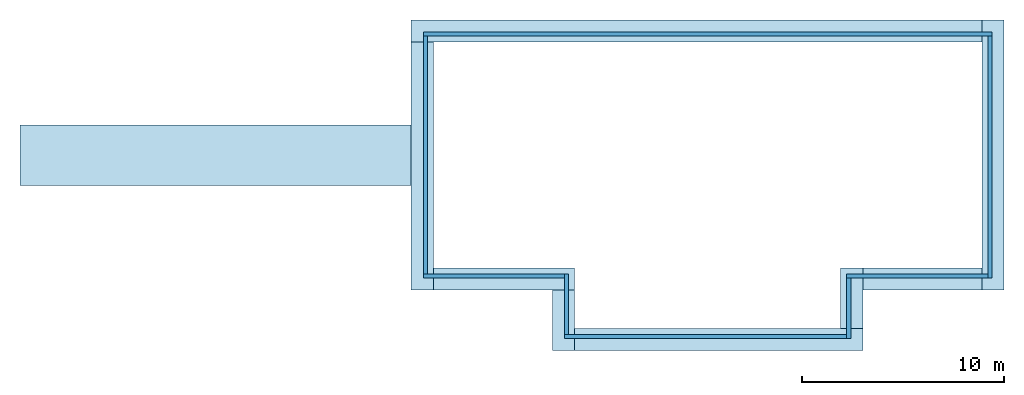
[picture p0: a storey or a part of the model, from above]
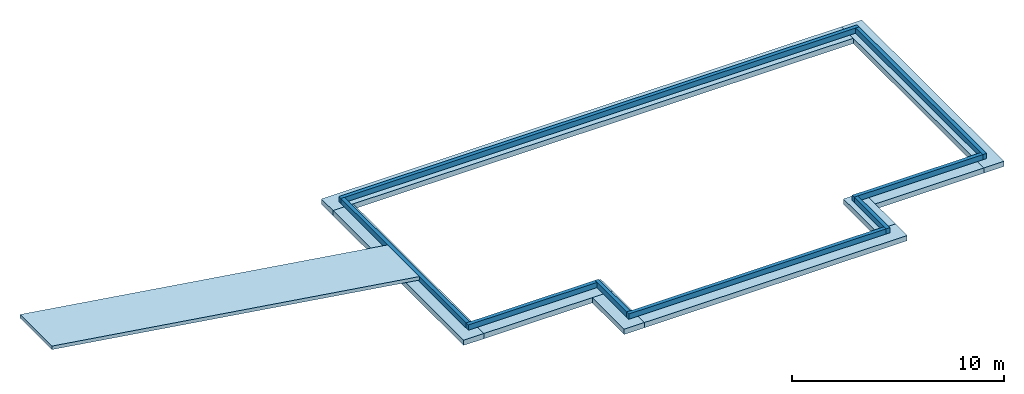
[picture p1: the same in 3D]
Properties of the parts of a building model (IFC2X3)

# File
Description: ViewDefinition [CoordinationView_V2.0, QuantityTakeOffAddOnView]
File name: Numéro de projet
Time: 2019-03-26T10:58:15
Written by: The EXPRESS Data Manager Version 5.02.0100.07 : 28 Aug 2013
Made in: 20180328_1600(x64) - Exporter 19.0.1.1 - Interface utilisateur alternative 19.0.1.1
Comment: STEP Physical File produced by: The EXPRESS Data Manager Version 5.02.0100.07 : 28 Aug 2013 * Module: EDMstepFileFactory/EDMstandAlone * Creation date: Tue Mar 26 10:58:15 2019 * Host: OCULUS-DGC * Database: C:\Users\TECHNI~1\AppData\Local\Temp\{1B9414DD-D0EE-45FC-AFBC-01F365118FDD}\ifc * Database version: 5507 * Database creation date: Tue Mar 26 10:58:10 2019 * Schema: IFC2X3 * Model: DataRepository.ifc * Model creation date: Tue Mar 26 10:58:10 2019 * Header model: DataRepository.ifc_HeaderModel * Header model creation date: Tue Mar 26 10:58:10 2019 * EDMuser: sdai-user * EDMgroup: sdai-group * License ID and type: 5605 : Permanent license. Expiry date: * EDMstepFileFactory options: 020000

# IfcProject, Numéro de projet
LongName: Nom du projet; Phase: Etat du projet

# IfcSite, Default
RefLatitude: 48, 51, 57, 604064; RefLongitude: 2, 19, 58, 799800; RefElevation: 0 m

# IfcBuilding
Pset_BuildingCommon - NumberOfStoreys: 9

# IfcBuildingStorey (9)
Name | LongName | Elevation (m)
Fondations | Fondations | -3.3
R-1 | R-1 | -3
Rez de Chaussée | Rez de Chaussée | 0
R+1 | R+1 | 3
R+2 | R+2 | 6
R+3 | R+3 | 9
R+4 | R+4 | 12
R+5 | R+5 | 15
R+6 | R+6 | 18

# IfcDoor: 1000 x 2000 mm (37)
Type - ParameterTakesPrecedence: no; Sizeable: no
OverallHeight: 2 m; OverallWidth: 1 m
Pset_DoorCommon - IsExternal: yes; Reference: 1000 x 2000 mm
BaseQuantities - Height: 2 m; Width: 1 m; Area: 2 m2
Name (M_Porte-Ouverture:1000 x 2000 mm:...) | In
454101 | R+1
454180 | R+1
454294 | R+1
454342 | R+1
454432 | R+1
454526 | R+1
456298 | R+2
456299 | R+2
456300 | R+2
456301 | R+2
456302 | R+2
456303 | R+2
456474 | R+3
456475 | R+3
456476 | R+3
456477 | R+3
456478 | R+3
456479 | R+3
456650 | R+4
456651 | R+4
456652 | R+4
456653 | R+4
456654 | R+4
456655 | R+4
456826 | R+5
456827 | R+5
456828 | R+5
456829 | R+5
456830 | R+5
456831 | R+5
457178 | Rez de Chaussée
457181 | Rez de Chaussée
457182 | Rez de Chaussée
457183 | Rez de Chaussée
461264 | R-1
466483 | R-1
466581 | R-1

# IfcDoor: 1600 x 2000 mm (7)
Type - ParameterTakesPrecedence: no; Sizeable: no
OverallHeight: 2 m; OverallWidth: 1.6 m
Pset_DoorCommon - IsExternal: yes; Reference: 1600 x 2000 mm
BaseQuantities - Height: 2 m; Width: 1.6 m; Area: 3.2 m2
Name (M_Porte-Ouverture:1600 x 2000 mm:...) | In
454836 | R+1
456304 | R+2
456480 | R+3
456656 | R+4
456832 | R+5
457184 | Rez de Chaussée
461265 | R-1

# IfcDoor: 2000 x 2000 mm (97)
Type - ParameterTakesPrecedence: no; Sizeable: no
OverallHeight: 2 m; OverallWidth: 2 m
Pset_DoorCommon - IsExternal: yes; Reference: 2000 x 2000 mm
BaseQuantities - Height: 2 m; Width: 2 m; Area: 4 m2
Name (M_Porte-Ouverture:2000 x 2000 mm:...) | In
451480 | R+1
451895 | R+1
452191 | R+1
452295 | R+1
452499 | R+1
452615 | R+1
452713 | R+1
452795 | R+1
452877 | R+1
452981 | R+1
453083 | R+1
453409 | R+1
453475 | R+1
453609 | R+1
453747 | R+1
453955 | R+1
456282 | R+2
456283 | R+2
456284 | R+2
456285 | R+2
456286 | R+2
456287 | R+2
456288 | R+2
456289 | R+2
456290 | R+2
456291 | R+2
456292 | R+2
456293 | R+2
456294 | R+2
456295 | R+2
456296 | R+2
456297 | R+2
456458 | R+3
456459 | R+3
456460 | R+3
456461 | R+3
456462 | R+3
456463 | R+3
456464 | R+3
456465 | R+3
456466 | R+3
456467 | R+3
456468 | R+3
456469 | R+3
456470 | R+3
456471 | R+3
456472 | R+3
456473 | R+3
456634 | R+4
456635 | R+4
456636 | R+4
456637 | R+4
456638 | R+4
456639 | R+4
456640 | R+4
456641 | R+4
456642 | R+4
456643 | R+4
456644 | R+4
456645 | R+4
456646 | R+4
456647 | R+4
456648 | R+4
456649 | R+4
456810 | R+5
456811 | R+5
456812 | R+5
456813 | R+5
456814 | R+5
456815 | R+5
456816 | R+5
456817 | R+5
456818 | R+5
456819 | R+5
456820 | R+5
456821 | R+5
456822 | R+5
456823 | R+5
456824 | R+5
456825 | R+5
457162 | Rez de Chaussée
457163 | Rez de Chaussée
457168 | Rez de Chaussée
457169 | Rez de Chaussée
457170 | Rez de Chaussée
457171 | Rez de Chaussée
457172 | Rez de Chaussée
457173 | Rez de Chaussée
457174 | Rez de Chaussée
457175 | Rez de Chaussée
457176 | Rez de Chaussée
457177 | Rez de Chaussée
459921 | Rez de Chaussée
460334 | Rez de Chaussée
460507 | Rez de Chaussée
460879 | Rez de Chaussée
461021 | Rez de Chaussée

# IfcDoor: 3000 x 2000 mm, M_Porte-Ouverture:3000 x 2000 mm:463773
In: R-1
Type - ParameterTakesPrecedence: no; Sizeable: no
OverallHeight: 2 m; OverallWidth: 3 m
Pset_DoorCommon - IsExternal: yes; Reference: 3000 x 2000 mm
BaseQuantities - Height: 2 m; Width: 3 m; Area: 6 m2

# IfcFooting: Semelle filante:Soubassement de soutènement - 300 x 600 x 300 (8)
In: Fondations
PredefinedType: STRIP_FOOTING
Name (Semelle filante:Soubassement de soutènement - 300 x 600 x 300:...)
463532
463540
463560
463574
463588
463598
463612
463626

# IfcMember: Limon à la française:Limon à la française - 50 mm de largeur (60)
Type - PredefinedType: STRINGER
Pset_MemberCommon - LoadBearing: yes; IsExternal: no; Reference: Contremarche 190 mm max marche 250 mm
BaseQuantities - NetSurfaceArea: 35.8411 m2; NetVolume: 0.668562 m3
Name (Escalier assemblé:Escalier:...) | In | Span (m) = Length (m) | Slope (deg) | CrossSectionArea (m2) | OuterSurfaceArea (m2) | GrossSurfaceArea (m2) | GrossVolume (m3)
467169 Stringer 1 | Rez de Chaussée | 0.05 | 0 | 0.899041 | 0.270884 | 2.06897 | 0.044952
467169 Stringer 2 | Rez de Chaussée | 0.05 | 0 | 0.899041 | 0.270884 | 2.06897 | 0.044952
467169 Stringer 3 | Rez de Chaussée | 0.05 | 0 | 0.97861 | 0.290776 | 2.248 | 0.0489305
467169 Stringer 4 | Rez de Chaussée | 0.05 | 0 | 0.97861 | 0.290776 | 2.248 | 0.0489305
467169 Stringer 5 | Rez de Chaussée
467169 Stringer 6 | Rez de Chaussée | 0.4 | 0 | 0.115 | 1.89657 | 2.12657 | 0.046
467169 Stringer 7 | Rez de Chaussée
467169 Stringer 8 | Rez de Chaussée
467169 Stringer 9 | Rez de Chaussée | 0.4 | 0 | 0.01 | 0.216569 | 0.236569 | 0.004
467169 Stringer 10 | Rez de Chaussée
468124 Stringer 1 | R+2 | 0.05 | 0 | 0.899041 | 0.270884 | 2.06897 | 0.044952
468124 Stringer 2 | R+2 | 0.05 | 0 | 0.899041 | 0.270884 | 2.06897 | 0.044952
468124 Stringer 3 | R+2 | 0.05 | 0 | 0.97861 | 0.290776 | 2.248 | 0.0489305
468124 Stringer 4 | R+2 | 0.05 | 0 | 0.97861 | 0.290776 | 2.248 | 0.0489305
468124 Stringer 5 | R+2
468124 Stringer 6 | R+2 | 0.4 | 0 | 0.115 | 1.89657 | 2.12657 | 0.046
468124 Stringer 7 | R+2
468124 Stringer 8 | R+2
468124 Stringer 9 | R+2 | 0.4 | 0 | 0.01 | 0.216569 | 0.236569 | 0.004
468124 Stringer 10 | R+2
468213 Stringer 1 | R+3 | 0.05 | 0 | 0.899041 | 0.270884 | 2.06897 | 0.044952
468213 Stringer 2 | R+3 | 0.05 | 0 | 0.899041 | 0.270884 | 2.06897 | 0.044952
468213 Stringer 3 | R+3 | 0.05 | 0 | 0.97861 | 0.290776 | 2.248 | 0.0489305
468213 Stringer 4 | R+3 | 0.05 | 0 | 0.97861 | 0.290776 | 2.248 | 0.0489305
468213 Stringer 5 | R+3
468213 Stringer 6 | R+3 | 0.4 | 0 | 0.115 | 1.89657 | 2.12657 | 0.046
468213 Stringer 7 | R+3
468213 Stringer 8 | R+3
468213 Stringer 9 | R+3 | 0.4 | 0 | 0.01 | 0.216569 | 0.236569 | 0.004
468213 Stringer 10 | R+3
468302 Stringer 1 | R+4 | 0.05 | 0 | 0.899041 | 0.270884 | 2.06897 | 0.044952
468302 Stringer 2 | R+4 | 0.05 | 0 | 0.899041 | 0.270884 | 2.06897 | 0.044952
468302 Stringer 3 | R+4 | 0.05 | 0 | 0.97861 | 0.290776 | 2.248 | 0.0489305
468302 Stringer 4 | R+4 | 0.05 | 0 | 0.97861 | 0.290776 | 2.248 | 0.0489305
468302 Stringer 5 | R+4
468302 Stringer 6 | R+4 | 0.4 | 0 | 0.115 | 1.89657 | 2.12657 | 0.046
468302 Stringer 7 | R+4
468302 Stringer 8 | R+4
468302 Stringer 9 | R+4 | 0.4 | 0 | 0.01 | 0.216569 | 0.236569 | 0.004
468302 Stringer 10 | R+4
468480 Stringer 1 | R-1 | 0.05 | 0 | 0.899041 | 0.270884 | 2.06897 | 0.044952
468480 Stringer 2 | R-1 | 0.05 | 0 | 0.899041 | 0.270884 | 2.06897 | 0.044952
468480 Stringer 3 | R-1 | 0.05 | 0 | 0.97861 | 0.290776 | 2.248 | 0.0489305
468480 Stringer 4 | R-1 | 0.05 | 0 | 0.97861 | 0.290776 | 2.248 | 0.0489305
468480 Stringer 5 | R-1
468480 Stringer 6 | R-1 | 0.4 | 0 | 0.115 | 1.89657 | 2.12657 | 0.046
468480 Stringer 7 | R-1
468480 Stringer 8 | R-1
468480 Stringer 9 | R-1 | 0.4 | 0 | 0.01 | 0.216569 | 0.236569 | 0.004
468480 Stringer 10 | R-1
468584 Stringer 1 | R+1 | 0.05 | 0 | 0.899041 | 0.270884 | 2.06897 | 0.044952
468584 Stringer 2 | R+1 | 0.05 | 0 | 0.899041 | 0.270884 | 2.06897 | 0.044952
468584 Stringer 3 | R+1 | 0.05 | 0 | 0.97861 | 0.290776 | 2.248 | 0.0489305
468584 Stringer 4 | R+1 | 0.05 | 0 | 0.97861 | 0.290776 | 2.248 | 0.0489305
468584 Stringer 5 | R+1
468584 Stringer 6 | R+1 | 0.4 | 0 | 0.115 | 1.89657 | 2.12657 | 0.046
468584 Stringer 7 | R+1
468584 Stringer 8 | R+1
468584 Stringer 9 | R+1 | 0.4 | 0 | 0.01 | 0.216569 | 0.236569 | 0.004
468584 Stringer 10 | R+1

# IfcOpeningElement: Opening (196)
BaseQuantities - Depth: 0.2 m
Name | In | Height (m) | Width (m)
Sol:Dalle pleine 200 mm:449392:2 | R+1 | 1.4 | 1.6
Sol:Dalle pleine 200 mm:449392:3 | R+1 | 0.95 | 1.6
Sol:Dalle pleine 200 mm:449392:4 | R+1 | 3.16 | 2.5
Sol:Dalle pleine 200 mm:456217:2 | R+2 | 1.4 | 1.6
Sol:Dalle pleine 200 mm:456217:3 | R+2 | 0.95 | 1.6
Sol:Dalle pleine 200 mm:456217:4 | R+2 | 3.16 | 2.5
Sol:Dalle pleine 200 mm:456393:2 | R+3 | 1.4 | 1.6
Sol:Dalle pleine 200 mm:456393:3 | R+3 | 0.95 | 1.6
Sol:Dalle pleine 200 mm:456393:4 | R+3 | 3.16 | 2.5
Sol:Dalle pleine 200 mm:456569:2 | R+4 | 1.4 | 1.6
Sol:Dalle pleine 200 mm:456569:3 | R+4 | 0.95 | 1.6
Sol:Dalle pleine 200 mm:456569:4 | R+4 | 3.16 | 2.5
Sol:Dalle pleine 200 mm:456745:2 | R+5 | 1.4 | 1.6
Sol:Dalle pleine 200 mm:456745:3 | R+5 | 0.95 | 1.6
Sol:Dalle pleine 200 mm:456745:4 | R+5 | 3.16 | 2.5
Sol:Dalle pleine 200 mm:457097:2 | Rez de Chaussée | 1.4 | 1.6
Sol:Dalle pleine 200 mm:457097:3 | Rez de Chaussée | 0.95 | 1.6
Sol:Dalle pleine 200 mm:457097:4 | Rez de Chaussée | 3.16 | 2.5
M_Porte-Ouverture:1000 x 2000 mm:466483:1 | R-1 | 1 | 2
M_Porte-Ouverture:2000 x 2000 mm:452877:1 | R+1 | 2 | 2
M_Porte-Ouverture:2000 x 2000 mm:452981:1 | R+1 | 2 | 2
M_Porte-Ouverture:2000 x 2000 mm:453083:1 | R+1 | 2 | 2
M_Porte-Ouverture:2000 x 2000 mm:453409:1 | R+1 | 2 | 2
M_Porte-Ouverture:2000 x 2000 mm:453475:1 | R+1 | 2 | 2
M_Porte-Ouverture:2000 x 2000 mm:453609:1 | R+1 | 2 | 2
M_Porte-Ouverture:2000 x 2000 mm:453747:1 | R+1 | 2 | 2
M_Porte-Ouverture:2000 x 2000 mm:453955:1 | R+1 | 2 | 2
M_Fenêtre-Ouverture carrée:0400 x 600mm:455751:1 | R+1 | 0.4 | 0.6
M_Fenêtre-Ouverture carrée:0400 x 600mm:455827:1 | R+1 | 0.4 | 0.6
M_Fenêtre-Ouverture carrée:0400 x 600mm:455913:1 | R+1 | 0.4 | 0.6
M_Porte-Ouverture:2000 x 2000 mm:452713:1 | R+1 | 2 | 2
M_Porte-Ouverture:2000 x 2000 mm:452795:1 | R+1 | 2 | 2
M_Porte-Ouverture:1000 x 2000 mm:454342:1 | R+1 | 1 | 2
M_Porte-Ouverture:2000 x 2000 mm:452191:1 | R+1 | 2 | 2
M_Porte-Ouverture:2000 x 2000 mm:452295:1 | R+1 | 2 | 2
M_Porte-Ouverture:2000 x 2000 mm:452499:1 | R+1 | 2 | 2
M_Porte-Ouverture:2000 x 2000 mm:452615:1 | R+1 | 2 | 2
M_Porte-Ouverture:1000 x 2000 mm:454101:1 | R+1 | 1 | 2
M_Porte-Ouverture:2000 x 2000 mm:451480:1 | R+1 | 2 | 2
M_Porte-Ouverture:2000 x 2000 mm:451895:1 | R+1 | 2 | 2
M_Fenêtre-Ouverture carrée:0400 x 600mm:455390:1 | R+1 | 0.4 | 0.6
M_Fenêtre-Ouverture carrée:0400 x 600mm:455557:1 | R+1 | 0.4 | 0.6
M_Fenêtre-Ouverture carrée:0400 x 600mm:455661:1 | R+1 | 0.4 | 0.6
M_Porte-Ouverture:1000 x 2000 mm:454432:1 | R+1 | 1 | 2
M_Porte-Ouverture:1000 x 2000 mm:454180:1 | R+1 | 1 | 2
M_Porte-Ouverture:1000 x 2000 mm:454526:1 | R+1 | 1 | 2
M_Porte-Ouverture:1600 x 2000 mm:454836:1 | R+1 | 1.6 | 2
M_Porte-Ouverture:1000 x 2000 mm:454294:1 | R+1 | 1 | 2
M_Porte-Ouverture:2000 x 2000 mm:456290:1 | R+2 | 2 | 2
M_Porte-Ouverture:2000 x 2000 mm:456291:1 | R+2 | 2 | 2
M_Porte-Ouverture:2000 x 2000 mm:456292:1 | R+2 | 2 | 2
M_Porte-Ouverture:2000 x 2000 mm:456293:1 | R+2 | 2 | 2
M_Porte-Ouverture:2000 x 2000 mm:456294:1 | R+2 | 2 | 2
M_Porte-Ouverture:2000 x 2000 mm:456295:1 | R+2 | 2 | 2
M_Porte-Ouverture:2000 x 2000 mm:456296:1 | R+2 | 2 | 2
M_Porte-Ouverture:2000 x 2000 mm:456297:1 | R+2 | 2 | 2
M_Fenêtre-Ouverture carrée:0400 x 600mm:456308:1 | R+2 | 0.4 | 0.6
M_Fenêtre-Ouverture carrée:0400 x 600mm:456309:1 | R+2 | 0.4 | 0.6
M_Fenêtre-Ouverture carrée:0400 x 600mm:456310:1 | R+2 | 0.4 | 0.6
M_Porte-Ouverture:2000 x 2000 mm:456288:1 | R+2 | 2 | 2
M_Porte-Ouverture:2000 x 2000 mm:456289:1 | R+2 | 2 | 2
M_Porte-Ouverture:1000 x 2000 mm:456301:1 | R+2 | 1 | 2
M_Porte-Ouverture:2000 x 2000 mm:456284:1 | R+2 | 2 | 2
M_Porte-Ouverture:2000 x 2000 mm:456285:1 | R+2 | 2 | 2
M_Porte-Ouverture:2000 x 2000 mm:456286:1 | R+2 | 2 | 2
M_Porte-Ouverture:2000 x 2000 mm:456287:1 | R+2 | 2 | 2
M_Porte-Ouverture:1000 x 2000 mm:456298:1 | R+2 | 1 | 2
M_Porte-Ouverture:2000 x 2000 mm:456282:1 | R+2 | 2 | 2
M_Porte-Ouverture:2000 x 2000 mm:456283:1 | R+2 | 2 | 2
M_Fenêtre-Ouverture carrée:0400 x 600mm:456305:1 | R+2 | 0.4 | 0.6
M_Fenêtre-Ouverture carrée:0400 x 600mm:456306:1 | R+2 | 0.4 | 0.6
M_Fenêtre-Ouverture carrée:0400 x 600mm:456307:1 | R+2 | 0.4 | 0.6
M_Porte-Ouverture:1000 x 2000 mm:456302:1 | R+2 | 1 | 2
M_Porte-Ouverture:1000 x 2000 mm:456299:1 | R+2 | 1 | 2
M_Porte-Ouverture:1000 x 2000 mm:456303:1 | R+2 | 1 | 2
M_Porte-Ouverture:1600 x 2000 mm:456304:1 | R+2 | 1.6 | 2
M_Porte-Ouverture:1000 x 2000 mm:456300:1 | R+2 | 1 | 2
M_Porte-Ouverture:2000 x 2000 mm:456466:1 | R+3 | 2 | 2
M_Porte-Ouverture:2000 x 2000 mm:456467:1 | R+3 | 2 | 2
M_Porte-Ouverture:2000 x 2000 mm:456468:1 | R+3 | 2 | 2
M_Porte-Ouverture:2000 x 2000 mm:456469:1 | R+3 | 2 | 2
M_Porte-Ouverture:2000 x 2000 mm:456470:1 | R+3 | 2 | 2
M_Porte-Ouverture:2000 x 2000 mm:456471:1 | R+3 | 2 | 2
M_Porte-Ouverture:2000 x 2000 mm:456472:1 | R+3 | 2 | 2
M_Porte-Ouverture:2000 x 2000 mm:456473:1 | R+3 | 2 | 2
M_Fenêtre-Ouverture carrée:0400 x 600mm:456484:1 | R+3 | 0.4 | 0.6
M_Fenêtre-Ouverture carrée:0400 x 600mm:456485:1 | R+3 | 0.4 | 0.6
M_Fenêtre-Ouverture carrée:0400 x 600mm:456486:1 | R+3 | 0.4 | 0.6
M_Porte-Ouverture:2000 x 2000 mm:456464:1 | R+3 | 2 | 2
M_Porte-Ouverture:2000 x 2000 mm:456465:1 | R+3 | 2 | 2
M_Porte-Ouverture:1000 x 2000 mm:456477:1 | R+3 | 1 | 2
M_Porte-Ouverture:2000 x 2000 mm:456460:1 | R+3 | 2 | 2
M_Porte-Ouverture:2000 x 2000 mm:456461:1 | R+3 | 2 | 2
M_Porte-Ouverture:2000 x 2000 mm:456462:1 | R+3 | 2 | 2
M_Porte-Ouverture:2000 x 2000 mm:456463:1 | R+3 | 2 | 2
M_Porte-Ouverture:1000 x 2000 mm:456474:1 | R+3 | 1 | 2
M_Porte-Ouverture:2000 x 2000 mm:456458:1 | R+3 | 2 | 2
M_Porte-Ouverture:2000 x 2000 mm:456459:1 | R+3 | 2 | 2
M_Fenêtre-Ouverture carrée:0400 x 600mm:456481:1 | R+3 | 0.4 | 0.6
M_Fenêtre-Ouverture carrée:0400 x 600mm:456482:1 | R+3 | 0.4 | 0.6
M_Fenêtre-Ouverture carrée:0400 x 600mm:456483:1 | R+3 | 0.4 | 0.6
M_Porte-Ouverture:1000 x 2000 mm:456478:1 | R+3 | 1 | 2
M_Porte-Ouverture:1000 x 2000 mm:456475:1 | R+3 | 1 | 2
M_Porte-Ouverture:1000 x 2000 mm:456479:1 | R+3 | 1 | 2
M_Porte-Ouverture:1600 x 2000 mm:456480:1 | R+3 | 1.6 | 2
M_Porte-Ouverture:1000 x 2000 mm:456476:1 | R+3 | 1 | 2
M_Porte-Ouverture:2000 x 2000 mm:456642:1 | R+4 | 2 | 2
M_Porte-Ouverture:2000 x 2000 mm:456643:1 | R+4 | 2 | 2
M_Porte-Ouverture:2000 x 2000 mm:456644:1 | R+4 | 2 | 2
M_Porte-Ouverture:2000 x 2000 mm:456645:1 | R+4 | 2 | 2
M_Porte-Ouverture:2000 x 2000 mm:456646:1 | R+4 | 2 | 2
M_Porte-Ouverture:2000 x 2000 mm:456647:1 | R+4 | 2 | 2
M_Porte-Ouverture:2000 x 2000 mm:456648:1 | R+4 | 2 | 2
M_Porte-Ouverture:2000 x 2000 mm:456649:1 | R+4 | 2 | 2
M_Fenêtre-Ouverture carrée:0400 x 600mm:456660:1 | R+4 | 0.4 | 0.6
M_Fenêtre-Ouverture carrée:0400 x 600mm:456661:1 | R+4 | 0.4 | 0.6
M_Fenêtre-Ouverture carrée:0400 x 600mm:456662:1 | R+4 | 0.4 | 0.6
M_Porte-Ouverture:2000 x 2000 mm:456640:1 | R+4 | 2 | 2
M_Porte-Ouverture:2000 x 2000 mm:456641:1 | R+4 | 2 | 2
M_Porte-Ouverture:1000 x 2000 mm:456653:1 | R+4 | 1 | 2
M_Porte-Ouverture:2000 x 2000 mm:456636:1 | R+4 | 2 | 2
M_Porte-Ouverture:2000 x 2000 mm:456637:1 | R+4 | 2 | 2
M_Porte-Ouverture:2000 x 2000 mm:456638:1 | R+4 | 2 | 2
M_Porte-Ouverture:2000 x 2000 mm:456639:1 | R+4 | 2 | 2
M_Porte-Ouverture:1000 x 2000 mm:456650:1 | R+4 | 1 | 2
M_Porte-Ouverture:2000 x 2000 mm:456634:1 | R+4 | 2 | 2
M_Porte-Ouverture:2000 x 2000 mm:456635:1 | R+4 | 2 | 2
M_Fenêtre-Ouverture carrée:0400 x 600mm:456657:1 | R+4 | 0.4 | 0.6
M_Fenêtre-Ouverture carrée:0400 x 600mm:456658:1 | R+4 | 0.4 | 0.6
M_Fenêtre-Ouverture carrée:0400 x 600mm:456659:1 | R+4 | 0.4 | 0.6
M_Porte-Ouverture:1000 x 2000 mm:456654:1 | R+4 | 1 | 2
M_Porte-Ouverture:1000 x 2000 mm:456651:1 | R+4 | 1 | 2
M_Porte-Ouverture:1000 x 2000 mm:456655:1 | R+4 | 1 | 2
M_Porte-Ouverture:1600 x 2000 mm:456656:1 | R+4 | 1.6 | 2
M_Porte-Ouverture:1000 x 2000 mm:456652:1 | R+4 | 1 | 2
M_Porte-Ouverture:2000 x 2000 mm:456818:1 | R+5 | 2 | 2
M_Porte-Ouverture:2000 x 2000 mm:456819:1 | R+5 | 2 | 2
M_Porte-Ouverture:2000 x 2000 mm:456820:1 | R+5 | 2 | 2
M_Porte-Ouverture:2000 x 2000 mm:456821:1 | R+5 | 2 | 2
M_Porte-Ouverture:2000 x 2000 mm:456822:1 | R+5 | 2 | 2
M_Porte-Ouverture:2000 x 2000 mm:456823:1 | R+5 | 2 | 2
M_Porte-Ouverture:2000 x 2000 mm:456824:1 | R+5 | 2 | 2
M_Porte-Ouverture:2000 x 2000 mm:456825:1 | R+5 | 2 | 2
M_Fenêtre-Ouverture carrée:0400 x 600mm:456836:1 | R+5 | 0.4 | 0.6
M_Fenêtre-Ouverture carrée:0400 x 600mm:456837:1 | R+5 | 0.4 | 0.6
M_Fenêtre-Ouverture carrée:0400 x 600mm:456838:1 | R+5 | 0.4 | 0.6
M_Porte-Ouverture:2000 x 2000 mm:456816:1 | R+5 | 2 | 2
M_Porte-Ouverture:2000 x 2000 mm:456817:1 | R+5 | 2 | 2
M_Porte-Ouverture:1000 x 2000 mm:456829:1 | R+5 | 1 | 2
M_Porte-Ouverture:2000 x 2000 mm:456812:1 | R+5 | 2 | 2
M_Porte-Ouverture:2000 x 2000 mm:456813:1 | R+5 | 2 | 2
M_Porte-Ouverture:2000 x 2000 mm:456814:1 | R+5 | 2 | 2
M_Porte-Ouverture:2000 x 2000 mm:456815:1 | R+5 | 2 | 2
M_Porte-Ouverture:1000 x 2000 mm:456826:1 | R+5 | 1 | 2
M_Porte-Ouverture:2000 x 2000 mm:456810:1 | R+5 | 2 | 2
M_Porte-Ouverture:2000 x 2000 mm:456811:1 | R+5 | 2 | 2
M_Fenêtre-Ouverture carrée:0400 x 600mm:456833:1 | R+5 | 0.4 | 0.6
M_Fenêtre-Ouverture carrée:0400 x 600mm:456834:1 | R+5 | 0.4 | 0.6
M_Fenêtre-Ouverture carrée:0400 x 600mm:456835:1 | R+5 | 0.4 | 0.6
M_Porte-Ouverture:1000 x 2000 mm:456830:1 | R+5 | 1 | 2
M_Porte-Ouverture:1000 x 2000 mm:456827:1 | R+5 | 1 | 2
M_Porte-Ouverture:1000 x 2000 mm:456831:1 | R+5 | 1 | 2
M_Porte-Ouverture:1600 x 2000 mm:456832:1 | R+5 | 1.6 | 2
M_Porte-Ouverture:1000 x 2000 mm:456828:1 | R+5 | 1 | 2
M_Porte-Ouverture:2000 x 2000 mm:457170:1 | Rez de Chaussée | 2 | 2
M_Porte-Ouverture:2000 x 2000 mm:457171:1 | Rez de Chaussée | 2 | 2
M_Porte-Ouverture:2000 x 2000 mm:457172:1 | Rez de Chaussée | 2 | 2
M_Porte-Ouverture:2000 x 2000 mm:457173:1 | Rez de Chaussée | 2 | 2
M_Porte-Ouverture:2000 x 2000 mm:457174:1 | Rez de Chaussée | 2 | 2
M_Porte-Ouverture:2000 x 2000 mm:457175:1 | Rez de Chaussée | 2 | 2
M_Porte-Ouverture:2000 x 2000 mm:457176:1 | Rez de Chaussée | 2 | 2
M_Porte-Ouverture:2000 x 2000 mm:457177:1 | Rez de Chaussée | 2 | 2
M_Fenêtre-Ouverture carrée:0400 x 600mm:457188:1 | Rez de Chaussée | 0.4 | 0.6
M_Fenêtre-Ouverture carrée:0400 x 600mm:457189:1 | Rez de Chaussée | 0.4 | 0.6
M_Fenêtre-Ouverture carrée:0400 x 600mm:457190:1 | Rez de Chaussée | 0.4 | 0.6
M_Porte-Ouverture:2000 x 2000 mm:457168:1 | Rez de Chaussée | 2 | 2
M_Porte-Ouverture:2000 x 2000 mm:457169:1 | Rez de Chaussée | 2 | 2
M_Porte-Ouverture:1000 x 2000 mm:457181:1 | Rez de Chaussée | 1 | 2
M_Porte-Ouverture:2000 x 2000 mm:460334:1 | Rez de Chaussée | 2 | 2
M_Porte-Ouverture:2000 x 2000 mm:460507:1 | Rez de Chaussée | 2 | 2
M_Porte-Ouverture:1000 x 2000 mm:457178:1 | Rez de Chaussée | 1 | 2
M_Porte-Ouverture:2000 x 2000 mm:457162:1 | Rez de Chaussée | 2 | 2
M_Porte-Ouverture:2000 x 2000 mm:457163:1 | Rez de Chaussée | 2 | 2
M_Fenêtre-Ouverture carrée:0400 x 600mm:457185:1 | Rez de Chaussée | 0.4 | 0.6
M_Fenêtre-Ouverture carrée:0400 x 600mm:457186:1 | Rez de Chaussée | 0.4 | 0.6
M_Fenêtre-Ouverture carrée:0400 x 600mm:457187:1 | Rez de Chaussée | 0.4 | 0.6
M_Porte-Ouverture:1000 x 2000 mm:457182:1 | Rez de Chaussée | 1 | 2
M_Porte-Ouverture:1000 x 2000 mm:457183:1 | Rez de Chaussée | 1 | 2
M_Porte-Ouverture:1600 x 2000 mm:457184:1 | Rez de Chaussée | 1.6 | 2
M_Porte-Ouverture:2000 x 2000 mm:459921:1 | Rez de Chaussée | 2 | 2
M_Porte-Ouverture:2000 x 2000 mm:460879:1 | Rez de Chaussée | 2 | 2
M_Porte-Ouverture:2000 x 2000 mm:461021:1 | Rez de Chaussée | 2 | 2
M_Porte-Ouverture:3000 x 2000 mm:463773:1 | R-1 | 3 | 2
M_Porte-Ouverture:1000 x 2000 mm:461264:1 | R-1 | 1 | 2
M_Porte-Ouverture:1600 x 2000 mm:461265:1 | R-1 | 1.6 | 2
M_Porte-Ouverture:1000 x 2000 mm:466581:1 | R-1 | 1 | 2

# IfcRailing: Garde-corps:900mm (12)
Pset_RailingCommon - IsExternal: no; Reference: 900mm; Height: 0.9 m
Name (Garde-corps:900mm:...) | In | Length (m)
467527 | Rez de Chaussée | 5.79573
467531 | Rez de Chaussée | 9.41253
468139 | R+2 | 5.79573
468143 | R+2 | 9.41253
468228 | R+3 | 5.79573
468232 | R+3 | 9.41253
468317 | R+4 | 5.79573
468321 | R+4 | 9.41253
468495 | R-1 | 5.79573
468499 | R-1 | 9.41253
468599 | R+1 | 5.79573
468603 | R+1 | 9.41253

# IfcSlab: Escalier assemblé:Contremarche 190 mm max marche 250 mm:176014 (6)
PredefinedType: LANDING
Pset_SlabCommon - IsExternal: no; PitchAngle: 0 deg; Reference: Palier non-monobloc
BaseQuantities - GrossArea: 3.0475 m2; GrossVolume: 0.152375 m3; Perimeter: 8.32 m; Width: 0.05 m
Name (Escalier assemblé:Escalier:...) | In
467169 Landing 1 | Rez de Chaussée
468124 Landing 1 | R+2
468213 Landing 1 | R+3
468302 Landing 1 | R+4
468480 Landing 1 | R-1
468584 Landing 1 | R+1

# IfcSlab: Sol:Balcon 160 mm (5)
PredefinedType: FLOOR; Material: Béton - Coulé sur place - Béton20 0.16 m
Pset_SlabCommon - LoadBearing: yes; IsExternal: no; Reference: Balcon 160 mm
Name (Sol:Balcon 160 mm:...) | In
450322 | R+1
456260 | R+2
456436 | R+3
456612 | R+4
456788 | R+5

# IfcSlab: Sol:Dalle pleine 200 mm (9)
PredefinedType: FLOOR; Material: Béton - Coulé sur place - Béton20 0.2 m
Pset_SlabCommon - LoadBearing: yes; Reference: Dalle pleine 200 mm; IsExternal: no
Name (Sol:Dalle pleine 200 mm:...) | In | GrossArea (m2) | Perimeter (m)
449392 | R+1 | 386.64 | 86.8
456217 | R+2 | 386.64 | 86.8
456393 | R+3 | 386.64 | 86.8
456569 | R+4 | 386.64 | 86.8
456745 | R+5 | 386.64 | 86.8
457097 | Rez de Chaussée | 386.64 | 86.8
461226 | R-1 | 386.64 | 86.8 | Pset_SlabCommon - PitchAngle: 0 deg; BaseQuantities - GrossVolume: 77.328 m3; Width: 0.2 m
463931 | Fondations | 60.6712 | 46.4475 | Pset_SlabCommon - PitchAngle: 0 deg; BaseQuantities - GrossVolume: 12.27 m3; Width: 0.202237 m
464137 | R+6 | 386.64 | 86.8 | Pset_SlabCommon - PitchAngle: 0 deg; BaseQuantities - GrossVolume: 77.328 m3; Width: 0.2 m

# IfcStair: Escalier assemblé:Contremarche 190 mm max marche 250 mm:176014 (6)
Pset_StairCommon - IsExternal: no; Reference: Contremarche 190 mm max marche 250 mm; NumberOfRiser: 16; NumberOfTreads: 14; RiserHeight: 0.188235 m; TreadLength: 0.25 m
Name (Escalier assemblé:Escalier:...) | In
467169 | Rez de Chaussée
468124 | R+2
468213 | R+3
468302 | R+4
468480 | R-1
468584 | R+1

# IfcStairFlight: Escalier assemblé:Contremarche 190 mm max marche 250 mm:176014 (12)
NumberOfRiser: 8; NumberOfTreads: 7; RiserHeight: 0.61757 m; TreadLength: 0.82021 m
Pset_StairFlightCommon - Reference: Marche 50 mm Contremarche 13 mm; NumberOfRiser: 16; NumberOfTreads: 14; RiserHeight: 0.188235 m; TreadLength: 0.25 m; TreadLengthAtOffset: 0.25 m; NosingLength: 0 m; WalkingLineOffset: 0.5 m; WaistThickness: 1 m
Name (Escalier assemblé:Escalier:...) | In
467169 Run 1 | Rez de Chaussée
467169 Run 2 | Rez de Chaussée
468124 Run 1 | R+2
468124 Run 2 | R+2
468213 Run 1 | R+3
468213 Run 2 | R+3
468302 Run 1 | R+4
468302 Run 2 | R+4
468480 Run 1 | R-1
468480 Run 2 | R-1
468584 Run 1 | R+1
468584 Run 2 | R+1

# IfcWallStandardCase: Mur de base:Générique - 150 mm (14)
Type - PredefinedType: STANDARD; Material: Blocs béton manufacturés 0.15 m
BaseQuantities - Width: 0.15 m
Pset_WallCommon - LoadBearing: yes; ExtendToStructure: no; IsExternal: yes; Reference: Générique - 150 mm; ThermalTransmittance: 8.66667 kg/K/s3
Name (Mur de base:Générique - 150 mm:...) | In | Height (m) | Length (m) | GrossFootprintArea (m2) | GrossSideArea (m2) | GrossVolume (m3)
447200 | R+1 | 2.8 | 2.5 | 0.375 | 15.59 | 1.05
447342 | R+1 | 3 | 1.6 | 0.24 | 10.98 | 0.72
456211 | R+2 | 2.8 | 2.5 | 0.375 | 15.59 | 1.05
456213 | R+2 | 3 | 1.6 | 0.24 | 10.98 | 0.72
456387 | R+3 | 2.8 | 2.5 | 0.375 | 15.59 | 1.05
456389 | R+3 | 3 | 1.6 | 0.24 | 10.98 | 0.72
456563 | R+4 | 2.8 | 2.5 | 0.375 | 15.59 | 1.05
456565 | R+4 | 3 | 1.6 | 0.24 | 10.98 | 0.72
456739 | R+5 | 2.8 | 2.5 | 0.375 | 15.59 | 1.05
456741 | R+5 | 3 | 1.6 | 0.24 | 10.98 | 0.72
457091 | Rez de Chaussée | 2.8 | 2.5 | 0.375 | 15.59 | 1.05
457093 | Rez de Chaussée | 3 | 1.6 | 0.24 | 10.98 | 0.72
461220 | R-1 | 2.8 | 2.5 | 0.375 | 15.59 | 1.05
461222 | R-1 | 2.8 | 1.6 | 0.24 | 10.28 | 0.672

# IfcWallStandardCase: Mur de base:Générique - 200 mm (93)
Type - PredefinedType: STANDARD; Material: Béton - Coulé sur place - Béton20 0.2 m
BaseQuantities - Width: 0.2 m
Pset_WallCommon - Reference: Générique - 200 mm; LoadBearing: yes; ExtendToStructure: no; IsExternal: yes
Name (Mur de base:Générique - 200 mm:...) | In | Height (m) | Length (m) | GrossFootprintArea (m2) | GrossSideArea (m2) | GrossVolume (m3)
445545 | R+1 | 2.8 | 28.2 | 5.64 | 112.72 | 9.392
445684 | R+1 | 2.8 | 12 | 2.4 | 72.88 | 6.576
445779 | R+1 | 2.8 | 6.8 | 1.36 | 27.52 | 2.208
445868 | R+1 | 2.8 | 15 | 3 | 87.92 | 8
446047 | R+1 | 2.8 | 14 | 2.8 | 56.32 | 4.64
446108 | R+1 | 2.8 | 14.8 | 2.96 | 86.72 | 7.888
446185 | R+1 | 2.8 | 7 | 1.4 | 28.72 | 2.32
446292 | R+1 | 2.8 | 11.8 | 2.36 | 71.68 | 6.464
446712 | R+1 | 2.8 | 13.8 | 2.76 | 80.72 | 7.328
446815 | R+1 | 2.8 | 13.8 | 2.76 | 71.92 | 6.288
446951 | R+1 | 2.8 | 8.3 | 1.66 | 48.04 | 4.288
447029 | R+1 | 2.8 | 6.8 | 1.36 | 41.92 | 3.808
456187 | R+2 | 2.8 | 28.2 | 5.64 | 112.72 | 9.392
456189 | R+2 | 2.8 | 12 | 2.4 | 72.88 | 6.576
456191 | R+2 | 2.8 | 6.8 | 1.36 | 27.52 | 2.208
456193 | R+2 | 2.8 | 15 | 3 | 87.92 | 8
456195 | R+2 | 2.8 | 14 | 2.8 | 56.32 | 4.64
456197 | R+2 | 2.8 | 14.8 | 2.96 | 86.72 | 7.888
456199 | R+2 | 2.8 | 7 | 1.4 | 28.72 | 2.32
456201 | R+2 | 2.8 | 11.8 | 2.36 | 71.68 | 6.464
456203 | R+2 | 2.8 | 13.8 | 2.76 | 80.72 | 7.328
456205 | R+2 | 2.8 | 13.8 | 2.76 | 71.92 | 6.288
456207 | R+2 | 2.8 | 8.3 | 1.66 | 48.04 | 4.288
456209 | R+2 | 2.8 | 6.8 | 1.36 | 41.92 | 3.808
456363 | R+3 | 2.8 | 28.2 | 5.64 | 112.72 | 9.392
456365 | R+3 | 2.8 | 12 | 2.4 | 72.88 | 6.576
456367 | R+3 | 2.8 | 6.8 | 1.36 | 27.52 | 2.208
456369 | R+3 | 2.8 | 15 | 3 | 87.92 | 8
456371 | R+3 | 2.8 | 14 | 2.8 | 56.32 | 4.64
456373 | R+3 | 2.8 | 14.8 | 2.96 | 86.72 | 7.888
456375 | R+3 | 2.8 | 7 | 1.4 | 28.72 | 2.32
456377 | R+3 | 2.8 | 11.8 | 2.36 | 71.68 | 6.464
456379 | R+3 | 2.8 | 13.8 | 2.76 | 80.72 | 7.328
456381 | R+3 | 2.8 | 13.8 | 2.76 | 71.92 | 6.288
456383 | R+3 | 2.8 | 8.3 | 1.66 | 48.04 | 4.288
456385 | R+3 | 2.8 | 6.8 | 1.36 | 41.92 | 3.808
456539 | R+4 | 2.8 | 28.2 | 5.64 | 112.72 | 9.392
456541 | R+4 | 2.8 | 12 | 2.4 | 72.88 | 6.576
456543 | R+4 | 2.8 | 6.8 | 1.36 | 27.52 | 2.208
456545 | R+4 | 2.8 | 15 | 3 | 87.92 | 8
456547 | R+4 | 2.8 | 14 | 2.8 | 56.32 | 4.64
456549 | R+4 | 2.8 | 14.8 | 2.96 | 86.72 | 7.888
456551 | R+4 | 2.8 | 7 | 1.4 | 28.72 | 2.32
456553 | R+4 | 2.8 | 11.8 | 2.36 | 71.68 | 6.464
456555 | R+4 | 2.8 | 13.8 | 2.76 | 80.72 | 7.328
456557 | R+4 | 2.8 | 13.8 | 2.76 | 71.92 | 6.288
456559 | R+4 | 2.8 | 8.3 | 1.66 | 48.04 | 4.288
456561 | R+4 | 2.8 | 6.8 | 1.36 | 41.92 | 3.808
456715 | R+5 | 2.8 | 28.2 | 5.64 | 112.72 | 9.392
456717 | R+5 | 2.8 | 12 | 2.4 | 72.88 | 6.576
456719 | R+5 | 2.8 | 6.8 | 1.36 | 27.52 | 2.208
456721 | R+5 | 2.8 | 15 | 3 | 87.92 | 8
456723 | R+5 | 2.8 | 14 | 2.8 | 56.32 | 4.64
456725 | R+5 | 2.8 | 14.8 | 2.96 | 86.72 | 7.888
456727 | R+5 | 2.8 | 7 | 1.4 | 28.72 | 2.32
456729 | R+5 | 2.8 | 11.8 | 2.36 | 71.68 | 6.464
456731 | R+5 | 2.8 | 13.8 | 2.76 | 80.72 | 7.328
456733 | R+5 | 2.8 | 13.8 | 2.76 | 71.92 | 6.288
456735 | R+5 | 2.8 | 8.3 | 1.66 | 48.04 | 4.288
456737 | R+5 | 2.8 | 6.8 | 1.36 | 41.92 | 3.808
457067 | Rez de Chaussée | 2.8 | 28.2 | 5.64 | 112.72 | 9.392
457069 | Rez de Chaussée | 2.8 | 12 | 2.4 | 72.88 | 6.576
457071 | Rez de Chaussée | 2.8 | 6.8 | 1.36 | 27.52 | 2.208
457073 | Rez de Chaussée | 2.8 | 15 | 3 | 87.92 | 8
457075 | Rez de Chaussée | 2.8 | 14 | 2.8 | 72.16 | 6.4
457077 | Rez de Chaussée | 2.8 | 14.8 | 2.96 | 86.72 | 7.888
457079 | Rez de Chaussée | 2.8 | 7 | 1.4 | 28.72 | 2.32
457081 | Rez de Chaussée | 2.8 | 11.8 | 2.36 | 71.68 | 6.464
457083 | Rez de Chaussée | 2.8 | 13.8 | 2.76 | 80.72 | 7.328
457085 | Rez de Chaussée | 2.8 | 13.8 | 2.76 | 68.64 | 5.968
457087 | Rez de Chaussée | 2.8 | 8.3 | 1.66 | 50.92 | 4.648
457089 | Rez de Chaussée | 2.8 | 6.8 | 1.36 | 35.44 | 3.088
460163 | Rez de Chaussée | 2.8 | 8.3 | 1.66 | 44.44 | 3.928
461196 | R-1 | 2.8 | 28.2 | 5.64 | 170.32 | 15.792
461198 | R-1 | 2.8 | 12 | 2.4 | 73.12 | 6.72
461200 | R-1 | 2.8 | 6.8 | 1.36 | 41.92 | 3.808
461202 | R-1 | 2.8 | 3.2 | 0.64 | 20.32 | 1.792
461204 | R-1 | 2.8 | 14 | 2.8 | 85.12 | 7.84
461206 | R-1 | 2.8 | 3 | 0.6 | 19.12 | 1.68
461208 | R-1 | 2.8 | 7 | 1.4 | 43.12 | 3.92
461210 | R-1 | 2.8 | 11.8 | 2.36 | 61.84 | 5.528
461214 | R-1 | 2.8 | 7.2 | 1.44 | 35.52 | 2.992
461216 | R-1 | 2.8 | 8.3 | 1.66 | 48.04 | 4.288
461218 | R-1 | 2.8 | 6.8 | 1.36 | 39.04 | 3.448
462374 | Fondations | 0.3 | 28.2 | 5.64 | 28.32 | 1.692
462513 | Fondations | 0.3 | 12 | 2.4 | 12.12 | 0.72
462606 | Fondations | 0.3 | 7 | 1.4 | 7.12 | 0.42
462695 | Fondations | 0.3 | 3 | 0.6 | 3.12 | 0.18
462837 | Fondations | 0.3 | 14 | 2.8 | 14.12 | 0.84
462912 | Fondations | 0.3 | 3 | 0.6 | 3.12 | 0.18
462969 | Fondations | 0.3 | 7 | 1.4 | 7.12 | 0.42
463102 | Fondations | 0.3 | 11.8 | 2.36 | 11.92 | 0.708
466271 | R-1 | 2.8 | 5.3 | 1.06 | 32.92 | 2.968

# IfcWindow: 0400 x 600mm (36)
Type - ParameterTakesPrecedence: no; Sizeable: no
OverallHeight: 0.6 m; OverallWidth: 0.4 m
Pset_WindowCommon - IsExternal: yes; Reference: 0400 x 600mm
BaseQuantities - Height: 0.6 m; Width: 0.4 m; Area: 0.24 m2
Name (M_Fenêtre-Ouverture carrée:0400 x 600mm:...) | In
455390 | R+1
455557 | R+1
455661 | R+1
455751 | R+1
455827 | R+1
455913 | R+1
456305 | R+2
456306 | R+2
456307 | R+2
456308 | R+2
456309 | R+2
456310 | R+2
456481 | R+3
456482 | R+3
456483 | R+3
456484 | R+3
456485 | R+3
456486 | R+3
456657 | R+4
456658 | R+4
456659 | R+4
456660 | R+4
456661 | R+4
456662 | R+4
456833 | R+5
456834 | R+5
456835 | R+5
456836 | R+5
456837 | R+5
456838 | R+5
457185 | Rez de Chaussée
457186 | Rez de Chaussée
457187 | Rez de Chaussée
457188 | Rez de Chaussée
457189 | Rez de Chaussée
457190 | Rez de Chaussée
